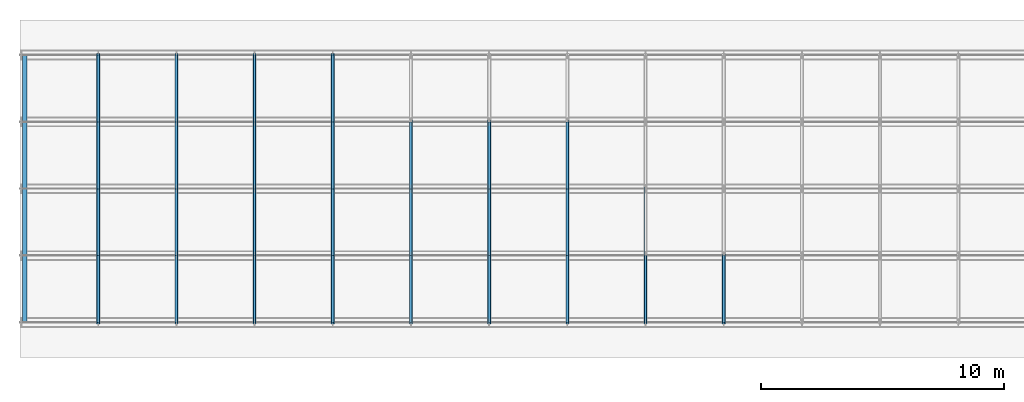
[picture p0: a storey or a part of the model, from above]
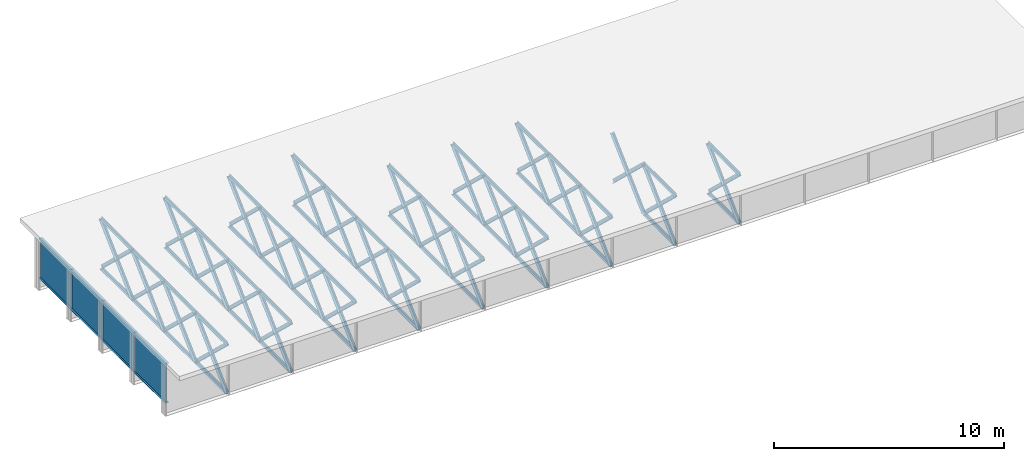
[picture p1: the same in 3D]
Properties of the parts of a building model (IFC4)

# File
Description: ViewDefinition [CoordinationView]
Time: 2026-06-10T16:02:29
Written by: IfcOpenShell 0.8.0
Made in: IfcOpenShell 0.8.0

# IfcMember (216)
In: Superstructure
Pset_OsdagBridgeProperties - Material: E250
Name | ProfileDepth_or_LegHeight | ProfileWidth_or_LegWidth | ConnectionType
8 x End Diaphragm | 2.091 | 0.195 | Pset_OsdagBridgeProperties - WebThickness: 0.018; FlangeThickness: 0.012
104 x Diagonal Brace | 0.196 | 0.13 | LONGER_LEG | Pset_OsdagBridgeProperties - ComponentRole: Intermediate Bracing Diagonal; BracingPattern: X; ProfileType: ANGLE; ProfileThickness: 0.008; StructuralSystem: Intermediate Bracing
52 x Bottom Chord |  |  | LONGER_LEG
52 x Top Chord |  |  | LONGER_LEG

# IfcPlate (185)
In: Superstructure
Pset_OsdagBridgeProperties - Material: E250
Name | ComponentRole | Thickness | Spacing
Girder Web 1 | Girder Web | 0.018 | Pset_OsdagBridgeProperties - SpanLength: 45; GirderSpacing: 2.75; Depth: 2.614
Top Flange 1 | Main Girder | Pset_OsdagBridgeProperties - SpanLength: 45; GirderSpacing: 2.75
Bottom Flange 1 | Main Girder | Pset_OsdagBridgeProperties - SpanLength: 45; GirderSpacing: 2.75
Girder Web 2 | Girder Web | 0.018 | Pset_OsdagBridgeProperties - SpanLength: 45; GirderSpacing: 2.75; Depth: 2.614
Top Flange 2 | Main Girder | Pset_OsdagBridgeProperties - SpanLength: 45; GirderSpacing: 2.75
Bottom Flange 2 | Main Girder | Pset_OsdagBridgeProperties - SpanLength: 45; GirderSpacing: 2.75
Girder Web 3 | Girder Web | 0.018 | Pset_OsdagBridgeProperties - SpanLength: 45; GirderSpacing: 2.75; Depth: 2.614
Top Flange 3 | Main Girder | Pset_OsdagBridgeProperties - SpanLength: 45; GirderSpacing: 2.75
Bottom Flange 3 | Main Girder | Pset_OsdagBridgeProperties - SpanLength: 45; GirderSpacing: 2.75
Girder Web 4 | Girder Web | 0.018 | Pset_OsdagBridgeProperties - SpanLength: 45; GirderSpacing: 2.75; Depth: 2.614
Top Flange 4 | Main Girder | Pset_OsdagBridgeProperties - SpanLength: 45; GirderSpacing: 2.75
Bottom Flange 4 | Main Girder | Pset_OsdagBridgeProperties - SpanLength: 45; GirderSpacing: 2.75
Girder Web 5 | Girder Web | 0.018 | Pset_OsdagBridgeProperties - SpanLength: 45; GirderSpacing: 2.75; Depth: 2.614
Top Flange 5 | Main Girder | Pset_OsdagBridgeProperties - SpanLength: 45; GirderSpacing: 2.75
Bottom Flange 5 | Main Girder | Pset_OsdagBridgeProperties - SpanLength: 45; GirderSpacing: 2.75
26 x Intermediate Stiffener 1 | Intermediate Stiffener | 0.012 | 3.214
8 x End Stiffener 1 | End Stiffener | 0.02
26 x Intermediate Stiffener 2 | Intermediate Stiffener | 0.012 | 3.214
8 x End Stiffener 2 | End Stiffener | 0.02
26 x Intermediate Stiffener 3 | Intermediate Stiffener | 0.012 | 3.214
8 x End Stiffener 3 | End Stiffener | 0.02
26 x Intermediate Stiffener 4 | Intermediate Stiffener | 0.012 | 3.214
8 x End Stiffener 4 | End Stiffener | 0.02
26 x Intermediate Stiffener 5 | Intermediate Stiffener | 0.012 | 3.214
8 x End Stiffener 5 | End Stiffener | 0.02

# IfcSlab, Deck Slab
In: Superstructure
Pset_OsdagBridgeProperties - ComponentRole: Deck Slab; DeckThickness: 0.23; CarriagewayWidth: 11; SpanLength: 45; SkewAngle: 0; Material: M30; fck_MPa: 30; fctm_MPa: 2.5; Ecm_GPa: 31
